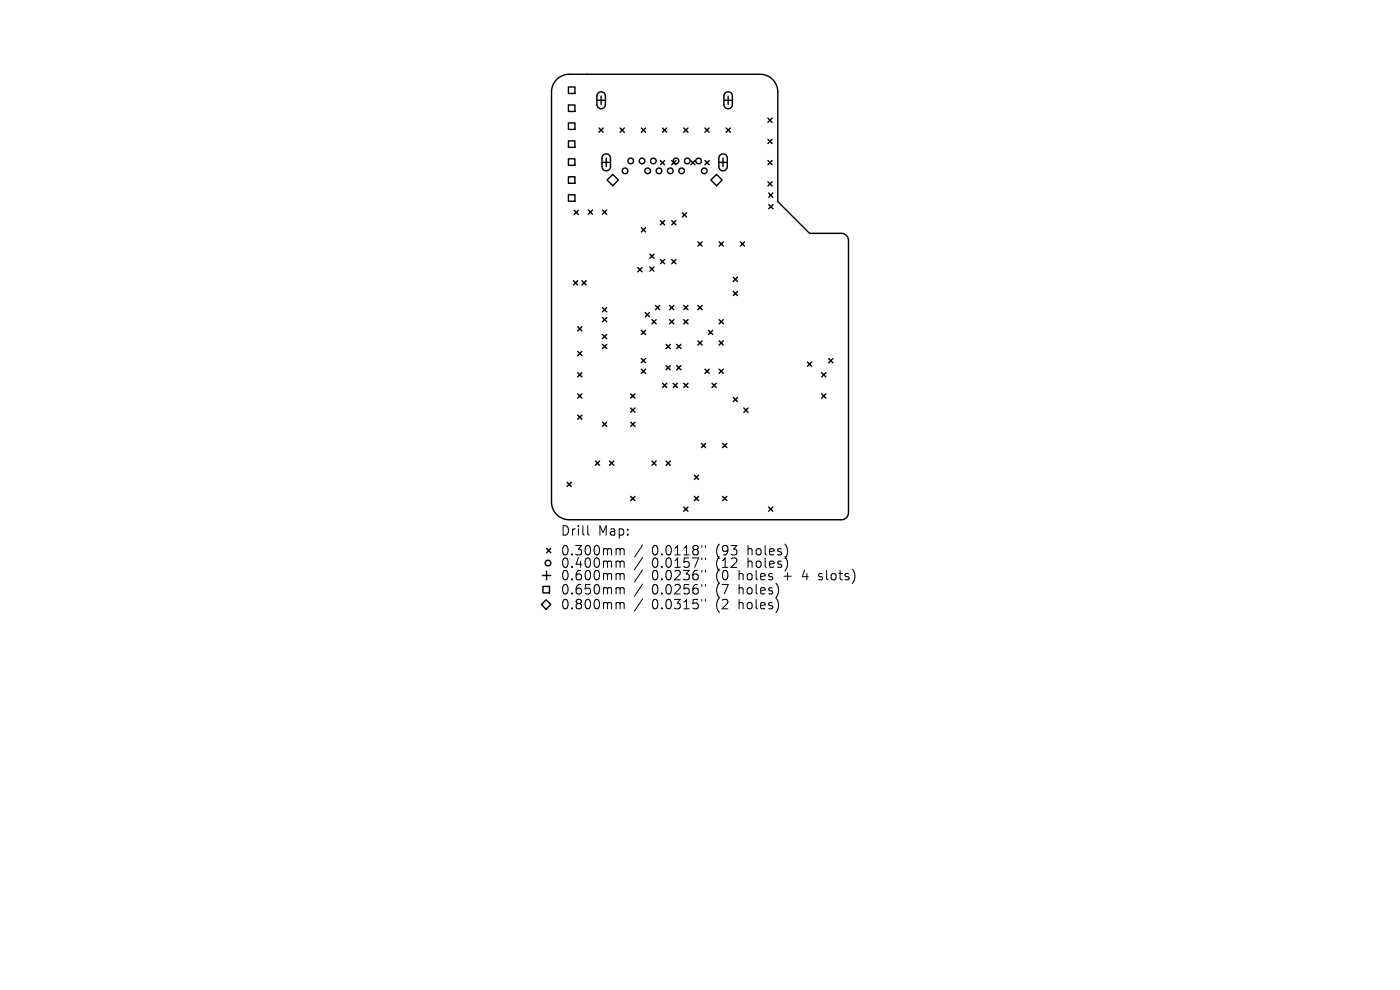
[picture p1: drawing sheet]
<svg xmlns="http://www.w3.org/2000/svg" width="297mm" height="210mm" viewBox="0 0 297 210" stroke-linecap="round" stroke-linejoin="round" font-family="sans-serif">
<defs><g id="words">
<g font-size="2.8">
<text x="118.9" y="113.9">Drill</text>
<text x="126.9" y="113.9">Map:</text>
<text x="118.9" y="118.1">0.300mm</text>
<text x="138.3" y="118.1">0.0118&quot;</text>
<text x="152" y="118.1">(93</text>
<text x="158.9" y="118.1">holes)</text>
<text x="118.9" y="120.7">0.400mm</text>
<text x="118.9" y="123.4">0.600mm</text>
<text x="138.3" y="120.7">0.0157&quot;</text>
<text x="138.3" y="123.4">0.0236&quot;</text>
<text x="152" y="120.7">(12</text>
<text x="152" y="123.4">(0</text>
<text x="157" y="123.4">holes</text>
<text x="158.9" y="120.7">holes)</text>
<text x="166.7" y="123.4">+</text>
<text x="170.9" y="123.4">4</text>
<text x="174.5" y="123.4">slots)</text>
<text x="118.9" y="126.4">0.650mm</text>
<text x="118.9" y="129.5">0.800mm</text>
<text x="138.3" y="126.4">0.0256&quot;</text>
<text x="138.3" y="129.5">0.0315&quot;</text>
<text x="152" y="126.4">(7</text>
<text x="152" y="129.5">(2</text>
<text x="157" y="126.4">holes)</text>
<text x="157" y="129.5">holes)</text>
</g>
</g></defs>
<g fill="none" stroke="#000" stroke-width=".3">
<path d="M118.1 16.9a3.8 3.8 0 0 1 2.7-1.1h40.5a3.8 3.8 0 0 1 3.7 3.7v23.3l6.8 6.7h6.7a1.5 1.5 0 0 1 1.5 1.5v57.8a1.5 1.5 0 0 1-1.5 1.5h-57.7a3.8 3.8 0 0 1-3.8-3.8v-87a3.8 3.8 0 0 1 1.1-2.6zM120.6 18.5h1.4v1.3h-1.4zM126.9 19.7a.9 .9 0 0 1 1-.2 .9 .9 0 0 1 .5 .9v1.8a.9 .9 0 0 1-.9 .9 .9 .9 0 0 1-.9-.9v-1.9zM153.8 19.7a.9 .9 0 0 1 1-.2 .9 .9 0 0 1 .6 .9v1.8a.9 .9 0 0 1-.9 .9 .9 .9 0 0 1-.9-.9v-1.9zM120.6 22.3h1.4v1.3h-1.4zM120.6 26.1h1.4v1.4h-1.4zM120.6 29.9h1.4v1.4h-1.4zM120.6 33.7h1.4v1.4h-1.4zM120.6 37.5h1.4v1.4h-1.4zM126.6 21.3h1.8M127.1 27.2l.9 .9M127.5 20.4v1.8"/>
<path d="M127.7 34.4h1.8M128 27.2l-.9 .9M128 32.9a.9 .9 0 0 1 1-.2 .9 .9 0 0 1 .5 .8v1.8a.9 .9 0 0 1-.9 .9 .9 .9 0 0 1-.9-.9v-1.8zM128.6 33.5v1.8M128.8 38.2l1.2-1.2 1.2 1.2-1.2 1.2zM131.6 27.2l.9 .9M132.5 27.2l-.9 .9M136.1 27.2l.9 .9M137 27.2l-.9 .9M140.1 34.1l.9 .9M140.6 27.2l.9 .9M141 34.1l-.9 .9"/>
<path d="M141.5 27.2l-.9 .9M142.5 34.1l.9 .9M143.4 34.1l-.9 .9M145.1 27.2l.9 .9M146 27.2l-.9 .9M146.6 34.1l.9 .9M147.5 34.1l-.9 .9M149.5 27.2l.9 .9M149.6 34.1l.9 .9M150.4 27.2l-.9 .9M150.5 34.1l-.9 .9M150.8 38.2l1.2-1.2 1.2 1.2-1.2 1.2z"/>
<path d="M152.5 34.4h1.8M152.8 32.9a.9 .9 0 0 1 .9-.2 .9 .9 0 0 1 .6 .8v1.8a.9 .9 0 0 1-.9 .9 .9 .9 0 0 1-.9-.9v-1.8zM153.4 33.5v1.8M153.6 21.3h1.8M154.1 27.2l.9 .9M154.5 20.4v1.8M155 27.2l-.9 .9M162.9 25.1l.9 .9M162.9 29.6l.9 .9M162.9 34.1l.9 .9M162.9 38.6l.9 .9M163.8 25.1l-.9 .9"/>
<path d="M163.8 29.6l-.9 .9M163.8 34.1l-.9 .9M163.8 38.6l-.9 .9M120.6 41.3h1.4v1.4h-1.4zM121.7 59.6l.9 .9M121.8 44.6l.9 .9M122.6 59.6l-.9 .9M122.7 44.6l-.9 .9M123.5 59.6l.9 .9M124.4 59.6l-.9 .9M124.8 44.6l.9 .9M125.7 44.6l-.9 .9"/>
<path d="M127.8 44.6l.9 .9M128.7 44.6l-.9 .9M135.3 56.8l.9 .9M136.1 48.3l.9 .9M136.2 56.8l-.9 .9M137 48.3l-.9 .9M137.9 53.9l.9 .9M137.9 56.6l.9 .9M138.8 53.9l-.9 .9M138.8 56.6l-.9 .9M140.1 46.8l.9 .9M140.1 55.1l.9 .9"/>
<path d="M141 55.1l-.9 .9M141 46.8l-.9 .9M142.5 46.8l.9 .9M142.5 55.1l.9 .9M143.4 46.8l-.9 .9M143.4 55.1l-.9 .9M144.7 45.1l.9 .9M145.6 45.1l-.9 .9M148.1 51.3l.9 .9M149 51.3l-.9 .9M152.6 51.3l.9 .9M153.5 51.3l-.9 .9"/>
<path d="M155.6 58.8l.9 .9M156.5 58.8l-.9 .9M157.1 51.3l.9 .9M158 51.3l-.9 .9M163.1 40.9l.9 .9M163.1 43.4l.9 .9M164 40.9l-.9 .9M164 43.4l-.9 .9M122.6 69.3l.9 .9M122.6 74.6l.9 .9M122.6 79.1l.9 .9M123.5 69.3l-.9 .9"/>
<path d="M123.5 74.6l-.9 .9M123.5 79.1l-.9 .9M127.8 65.3l.9 .9M127.8 67.4l.9 .9M127.8 71l.9 .9M127.8 73.1l.9 .9M128.7 65.3l-.9 .9M128.7 67.4l-.9 .9M128.7 71l-.9 .9M128.7 73.1l-.9 .9M136.1 70.1l.9 .9M136.1 76.1l.9 .9"/>
<path d="M136.1 78.3l.9 .9M136.9 66.3l.9 .9M137 70.1l-.9 .9M137 76.1l-.9 .9M137 78.3l-.9 .9M137.8 66.3l-.9 .9M138.3 67.8l.9 .9M139.1 64.8l.9 .9M139.2 67.8l-.9 .9M140 64.8l-.9 .9M141.3 73.1l.9 .9M141.3 77.6l.9 .9"/>
<path d="M142.1 64.8l.9 .9M142.1 67.8l.9 .9M142.2 73.1l-.9 .9M142.2 77.6l-.9 .9M143 64.8l-.9 .9M143 67.8l-.9 .9M143.6 77.6l.9 .9M143.6 73.1l.9 .9M144.5 73.1l-.9 .9M144.5 77.6l-.9 .9M145.1 67.8l.9 .9M145.1 64.8l.9 .9"/>
<path d="M146 64.8l-.9 .9M146 67.8l-.9 .9M148.1 64.8l.9 .9M148.1 72.3l.9 .9M149 72.3l-.9 .9M149 64.8l-.9 .9M149.6 78.3l.9 .9M150.3 70.1l.9 .9M150.5 78.3l-.9 .9M151.2 70.1l-.9 .9M152.6 78.3l.9 .9M152.6 72.3l.9 .9"/>
<path d="M152.6 67.8l.9 .9M153.5 67.8l-.9 .9M153.5 72.3l-.9 .9M153.5 78.3l-.9 .9M155.6 61.8l.9 .9M156.5 61.8l-.9 .9M171.3 76.8l.9 .9M172.2 76.8l-.9 .9M174.3 79.1l.9 .9M175.2 79.1l-.9 .9M175.8 76.1l.9 .9M176.7 76.1l-.9 .9"/>
<path d="M122.6 83.6l.9 .9M122.6 88.1l.9 .9M123.5 83.6l-.9 .9M123.5 88.1l-.9 .9M126.3 97.8l.9 .9M127.2 97.8l-.9 .9M127.8 89.6l.9 .9M128.7 89.6l-.9 .9M129.3 97.8l.9 .9M130.2 97.8l-.9 .9M133.8 83.6l.9 .9M133.8 86.6l.9 .9"/>
<path d="M133.8 89.6l.9 .9M134.7 83.6l-.9 .9M134.7 86.6l-.9 .9M134.7 89.6l-.9 .9M138.3 97.8l.9 .9M139.2 97.8l-.9 .9M140.6 81.3l.9 .9M141.3 97.8l.9 .9M141.5 81.3l-.9 .9M142.2 97.8l-.9 .9M142.8 81.3l.9 .9M143.7 81.3l-.9 .9"/>
<path d="M145.1 81.3l.9 .9M146 81.3l-.9 .9M148.8 94.1l.9 .9M149.7 94.1l-.9 .9M151.1 81.3l.9 .9M152 81.3l-.9 .9M153.3 94.1l.9 .9M154.2 94.1l-.9 .9M155.6 84.3l.9 .9M156.5 84.3l-.9 .9M157.8 86.6l.9 .9M158.7 86.6l-.9 .9"/>
<path d="M174.3 83.6l.9 .9M175.2 83.6l-.9 .9M116 116.4l.9 .9M116.9 116.4l-.9 .9M120.3 102.3l.9 .9M121.2 102.3l-.9 .9M133.8 105.3l.9 .9M134.7 105.3l-.9 .9M145.1 107.6l.9 .9M146 107.6l-.9 .9M147.3 100.8l.9 .9M147.3 105.3l.9 .9"/>
<path d="M148.2 105.3l-.9 .9M148.2 100.8l-.9 .9M153.3 105.3l.9 .9M154.2 105.3l-.9 .9M163.1 107.6l.9 .9M164 107.6l-.9 .9M114.9 128.2l1-1 1 1-1 1zM115.1 122.1h1.8M115.2 124.4h1.4v1.4h-1.4zM116 121.2v1.8"/>
<circle cx="132.6" cy="36.2" r=".6"/>
<circle cx="133.8" cy="34.1" r=".6"/>
<circle cx="136.2" cy="34.1" r=".6"/>
<circle cx="137.4" cy="36.2" r=".6"/>
<circle cx="138.6" cy="34.1" r=".6"/>
<circle cx="139.8" cy="36.2" r=".6"/>
<circle cx="142.2" cy="36.2" r=".6"/>
<circle cx="143.4" cy="34.1" r=".6"/>
<circle cx="144.6" cy="36.2" r=".6"/>
<circle cx="145.8" cy="34.1" r=".6"/>
<circle cx="148.2" cy="34.1" r=".6"/>
<circle cx="149.4" cy="36.2" r=".6"/>
<circle cx="116.3" cy="119.4" r=".6"/>
</g>
<g fill="none" stroke="#000" stroke-width=".21">
<path d="M124.7 111.5v1.7l.3 .3M131 116.4h.3l.3 .3M131 119h.3l.3 .3M131.6 116.7l.2-.3 .5 .1 .1 1.2M131.6 116.7v1M131.6 119.3v1.1M131.6 119.3l.2-.3 .5 .1 .1 1.3M136.3 115.6l-1.7 2.6M136.3 118.3l-1.7 2.5M148.9 115.7v.4M148.9 118.4v.3M149.6 115.7v.4"/>
<path d="M149.6 118.4v.3M131 121.7h.3l.3 .2M131 124.7h.3l.3 .2M131 127.8h.3l.3 .3M131.6 121.9v1.1M131.6 124.9v1.1M131.6 128.1v1M131.6 121.9l.2-.2 .5 .1 .1 1.2M131.6 124.9l.2-.2 .5 .1 .1 1.2M131.6 128.1l.2-.3 .5 .1 .1 1.2M136.3 120.9l-1.7 2.6M136.3 123.9l-1.7 2.6"/>
<path d="M136.3 127.1l-1.7 2.5M148.9 121v.4M148.9 124v.4M148.9 127.1v.4M149.6 121v.4M149.6 124v.4M149.6 127.1v.4M173.6 122.9l.2 .1M173.7 121.8v.4"/>
</g>
<use href="#words"/>
</svg>
